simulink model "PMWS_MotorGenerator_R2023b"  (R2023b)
settings: Solver=ode23t  StartTime=0.0  StopTime=660  FixedStep=0.001  EnableMultiTasking=on
StartFcn:
  | tic
StopFcn:
  | toc
  | %disp(['実時間の' num2str(max(tout)/toc) '倍速'])
libraries: fl_lib x7, nesl_utility x5, simulink x2, PMWS_Simscape_Library_lib x1

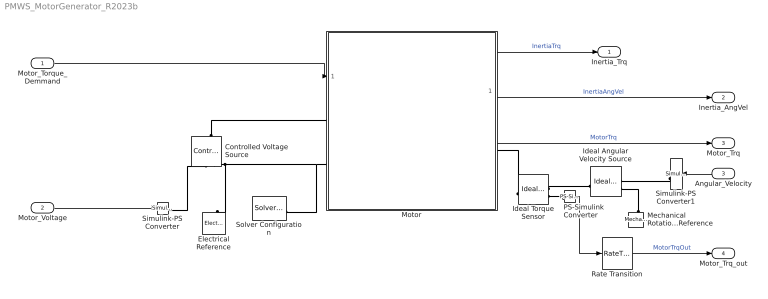
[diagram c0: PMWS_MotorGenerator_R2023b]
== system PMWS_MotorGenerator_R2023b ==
  Motor_Torque_Demmand : Inport
  Motor_Voltage : Inport  Port=2
  Angular_Velocity : Inport  Port=3
  Controlled Voltage Source : fl_lib/Electrical/Electrical Sources/Controlled Voltage Source
  Electrical Reference : fl_lib/Electrical/Electrical Elements/Electrical Reference
  Ideal Angular Velocity Source : fl_lib/Mechanical/Mechanical Sources/Ideal Angular Velocity Source
  Ideal Torque Sensor : fl_lib/Mechanical/Mechanical Sensors/Ideal Torque Sensor
  Mechanical Rotational Reference : fl_lib/Mechanical/Rotational Elements/Mechanical Rotational Reference
  Motor : Subsystem
  PS-Simulink Converter : nesl_utility/PS-Simulink Converter  PhysicalDomain=network_engine_domain  SubClassName=ps_output  LeftPortType=input  RightPortType=output  PseudoPeriodic=off  Frequencies=[]  VectorFormat=inherit  Unit=inherit  AffineConversion=off
  Rate Transition : RateTransition  OutPortSampleTime=0.001
  Simulink-PS Converter : nesl_utility/Simulink-PS Converter  PhysicalDomain=network_engine_domain  SubClassName=ps_input  LeftPortType=input  RightPortType=output  PseudoPeriodic=off  Frequencies=[]  NoiseDistribution=none  NoiseParameters=[]  Unit=1  AffineConversion=off  FilteringAndDerivatives=provide  SimscapeFilterOrder=1  InputFilterTimeConstant=0.001  UdotUserProvided=0
  Simulink-PS Converter1 : nesl_utility/Simulink-PS Converter  PhysicalDomain=network_engine_domain  SubClassName=ps_input  LeftPortType=input  RightPortType=output  PseudoPeriodic=off  Frequencies=[]  NoiseDistribution=none  NoiseParameters=[]  Unit=1  AffineConversion=off  FilteringAndDerivatives=filter  SimscapeFilterOrder=1  InputFilterTimeConstant=0.001  UdotUserProvided=1
  Solver Configuration : nesl_utility/Solver Configuration  PhysicalDomain=network_engine_domain  SubClassName=solver  LeftPortType=input  RightPortType=generic  Tones=[]  Harmonics=[]  SimulateNoise=off  Profile=off  UseLocalSampling=off  EnableSwitchedLinearOptims=on  FrequencyDomain=off  UseCCode=off  RelTol=0.001  AbsTol=1e-06  MinStep=1e-09  ToWorkspace=off  RevertToSquareIcSolve=off  NumHomotopyIterations=100  PhasorMode=off  PhasorModeNumHarmonics=1  ConsistencySolver=NEWTON_FTOL  IndexReductionMethod=DerivativeReplacement  DoDC=off  ResidualTolerance=1e-3  ConsistencyTolSource=GLOBAL  ConsistencyAbsTol=0.001  ConsistencyRelTol=0.001  ConsistencyTolFactor=0.001  UseLocalSolver=off  LocalSolverChoice=NE_BACKWARD_EULER_ADVANCER  ResolveIndetEquations=on  FunctionEvalNumThread=1  LocalSolverSampleTime=0.01  DoFixedCost=off  MaxNonlinIter=20  MaxModeIter=2  ComputeImpulses=off  ImpulseIterations=2  LinearAlgebra=Sparse  LinearAlgebraNumThread=0  EquationFormulation=NE_TIME_EF  DelaysMemoryBudget=1024  AutomaticFiltering=off  FilteringTimeConstant=0.001  PartitionStorageMethod=AS_NEEDED  PartitionMemoryBudget=1024  PartitionMethod=FAST  MultibodyUseLocalSolver=off  MultibodyLocalSolverChoice=ODE1  MultibodyLocalSolverSampleTime=0.001
  Inertia_Trq : Outport
  Inertia_AngVel : Outport  Port=2
  Motor_Trq : Outport  Port=3
  Motor_Trq_out : Outport  Port=4
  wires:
  Motor_Torque_Demmand/1 -> Motor/1(Motor Torque Demand [Nm])
  Angular_Velocity/1 -> Simulink-PS Converter1/1
  Motor/1(Inertia_Trq) -> Inertia_Trq/1  "InertiaTrq"
  Motor/2(Inertia_AngVel) -> Inertia_AngVel/1  "InertiaAngVel"
  Motor_Voltage/1 -> Simulink-PS Converter/1
  Motor/3(Motor_Trq) -> Motor_Trq/1  "MotorTrq"
  PS-Simulink Converter/1 -> Rate Transition/1
  Rate Transition/1 -> Motor_Trq_out/1  "MotorTrqOut"
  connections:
  Motor/LConn2 -- Controlled Voltage Source/RConn2 -- Electrical Reference/LConn1 -- Solver Configuration/RConn1
  Controlled Voltage Source/LConn1 -- Motor/LConn1
  Ideal Torque Sensor/RConn1 -- Ideal Angular Velocity Source/LConn1
  Simulink-PS Converter/RConn1 -- Controlled Voltage Source/RConn1
  Mechanical Rotational Reference/LConn1 -- Ideal Angular Velocity Source/RConn2
  Simulink-PS Converter1/RConn1 -- Ideal Angular Velocity Source/RConn1
  Ideal Torque Sensor/LConn1 -- Motor/RConn1
  PS-Simulink Converter/LConn1 -- Ideal Torque Sensor/RConn2

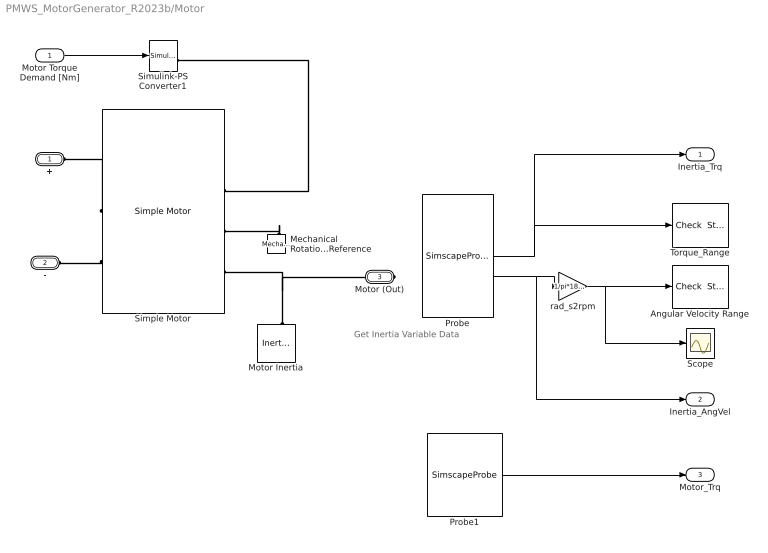
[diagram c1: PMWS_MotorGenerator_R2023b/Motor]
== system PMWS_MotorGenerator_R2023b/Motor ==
  note: Get Inertia Variable Data
  Motor Torque Demand [Nm] : Inport
  Angular Velocity Range : simulink/Model Verification/Check  Static Range  Description=0 <= u <= 10000  Commented=on  max=10000  max_included=on  min=0  min_included=on  enabled=on  stopWhenAssertionFail=off  export=off  icon=graphic
  Mechanical Rotational Reference : fl_lib/Mechanical/Rotational Elements/Mechanical Rotational Reference
  Motor Inertia : fl_lib/Mechanical/Rotational Elements/Inertia  inertia=0.1 kg*m^2  num_ports=foundation.enum.numPorts2.one  w_specify=on  w_priority=High  w=0 rad/s  w_nominal_specify=off  w_nominal_unit=rad/s  w_nominal_value=1  t_specify=off  t_priority=High  t=0 N*m  t_nominal_specify=off  t_nominal_unit=N*m  t_nominal_value=1
  Probe : SimscapeProbe  BoundBlock=415  Variables={t, w}
  Probe1 : SimscapeProbe  BoundBlock=5477  Variables={T}
  Scope : Scope
  Simple Motor : PMWS_Simscape_Library_lib/PowerTrain/Simple Motor  Efficiency=0.9  I_max=300 A  I_specify=on  I_priority=High  I=0 A  I_nominal_specify=off  I_nominal_unit=A  I_nominal_value=1  I_temp_specify=off  I_temp_priority=None  I_temp=0 A  I_temp_nominal_specify=off  I_temp_nominal_unit=A  I_temp_nominal_value=1  V_specify=off  V_priority=High  V=0 V  V_nominal_specify=off  V_nominal_unit=V  V_nominal_value=1  T_specify=off  T_priority=High  T=0 N*m  T_nominal_specify=off  T_nominal_unit=N*m  T_nominal_value=1  W_specify=off  W_priority=High  W=0 rad/s  W_nominal_specify=off  W_nominal_unit=rad/s  W_nominal_value=1
  Simulink-PS Converter1 : nesl_utility/Simulink-PS Converter  PhysicalDomain=network_engine_domain  SubClassName=ps_input  LeftPortType=input  RightPortType=output  PseudoPeriodic=off  Frequencies=[]  NoiseDistribution=none  NoiseParameters=[]  Unit=N*m  AffineConversion=off  FilteringAndDerivatives=filter  SimscapeFilterOrder=1  InputFilterTimeConstant=.01  UdotUserProvided=1
  Torque_Range : simulink/Model Verification/Check  Static Range  Description=0 <= u <= 300  Commented=on  max=300  max_included=on  min=0  min_included=on  enabled=on  stopWhenAssertionFail=off  export=off  icon=graphic
  rad_s2rpm : Gain  Gain=1/pi*180/60
  + : PMIOPort  Side=Left
  - : PMIOPort  Port=2  Side=Left
  Motor (Out) : PMIOPort  Port=3  Side=Right
  Inertia_Trq : Outport
  Inertia_AngVel : Outport  Port=2
  Motor_Trq : Outport  Port=3
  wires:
  Motor Torque Demand [Nm]/1 -> Simulink-PS Converter1/1
  Probe/1 -> Torque_Range/1, Inertia_Trq/1
  Probe/2 -> Inertia_AngVel/1, rad_s2rpm/1
  rad_s2rpm/1 -> Scope/1, Angular Velocity Range/1
  Probe1/1 -> Motor_Trq/1
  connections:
  Simple Motor/RConn1 -- Simulink-PS Converter1/RConn1
  Motor Inertia/LConn1 -- Simple Motor/RConn3 -- Motor (Out)/RConn1
  Simple Motor/LConn1 -- +/RConn1
  Simple Motor/LConn2 -- -/RConn1
  Mechanical Rotational Reference/LConn1 -- Simple Motor/RConn2
